VERSION 5.7 ;
  NOWIREEXTENSIONATPIN ON ;
  DIVIDERCHAR "/" ;
  BUSBITCHARS "[]" ;
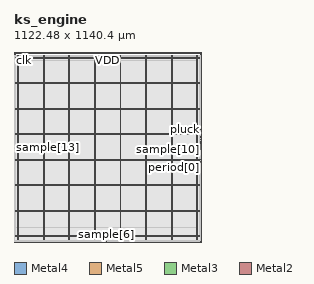
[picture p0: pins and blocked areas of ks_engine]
MACRO ks_engine
  CLASS BLOCK ;
  FOREIGN ks_engine ;
  ORIGIN 0.000 0.000 ;
  SIZE 1122.480 BY 1140.400 ;
  PIN VDD
    DIRECTION INOUT ;
    USE POWER ;
    PORT
      LAYER Metal4 ;
        RECT 22.240 15.380 23.840 1121.420 ;
    END
    PORT
      LAYER Metal4 ;
        RECT 175.840 15.380 177.440 1121.420 ;
    END
    PORT
      LAYER Metal4 ;
        RECT 329.440 15.380 331.040 1121.420 ;
    END
    PORT
      LAYER Metal4 ;
        RECT 483.040 15.380 484.640 1121.420 ;
    END
    PORT
      LAYER Metal4 ;
        RECT 636.640 15.380 638.240 1121.420 ;
    END
    PORT
      LAYER Metal4 ;
        RECT 790.240 15.380 791.840 1121.420 ;
    END
    PORT
      LAYER Metal4 ;
        RECT 943.840 15.380 945.440 1121.420 ;
    END
    PORT
      LAYER Metal4 ;
        RECT 1097.440 15.380 1099.040 1121.420 ;
    END
    PORT
      LAYER Metal5 ;
        RECT 6.720 31.530 1115.520 33.130 ;
    END
    PORT
      LAYER Metal5 ;
        RECT 6.720 184.710 1115.520 186.310 ;
    END
    PORT
      LAYER Metal5 ;
        RECT 6.720 337.890 1115.520 339.490 ;
    END
    PORT
      LAYER Metal5 ;
        RECT 6.720 491.070 1115.520 492.670 ;
    END
    PORT
      LAYER Metal5 ;
        RECT 6.720 644.250 1115.520 645.850 ;
    END
    PORT
      LAYER Metal5 ;
        RECT 6.720 797.430 1115.520 799.030 ;
    END
    PORT
      LAYER Metal5 ;
        RECT 6.720 950.610 1115.520 952.210 ;
    END
    PORT
      LAYER Metal5 ;
        RECT 6.720 1103.790 1115.520 1105.390 ;
    END
  END VDD
  PIN VSS
    DIRECTION INOUT ;
    USE GROUND ;
    PORT
      LAYER Metal4 ;
        RECT 25.540 15.380 27.140 1121.420 ;
    END
    PORT
      LAYER Metal4 ;
        RECT 179.140 15.380 180.740 1121.420 ;
    END
    PORT
      LAYER Metal4 ;
        RECT 332.740 15.380 334.340 1121.420 ;
    END
    PORT
      LAYER Metal4 ;
        RECT 486.340 15.380 487.940 1121.420 ;
    END
    PORT
      LAYER Metal4 ;
        RECT 639.940 15.380 641.540 1121.420 ;
    END
    PORT
      LAYER Metal4 ;
        RECT 793.540 15.380 795.140 1121.420 ;
    END
    PORT
      LAYER Metal4 ;
        RECT 947.140 15.380 948.740 1121.420 ;
    END
    PORT
      LAYER Metal4 ;
        RECT 1100.740 15.380 1102.340 1121.420 ;
    END
    PORT
      LAYER Metal5 ;
        RECT 6.720 34.830 1115.520 36.430 ;
    END
    PORT
      LAYER Metal5 ;
        RECT 6.720 188.010 1115.520 189.610 ;
    END
    PORT
      LAYER Metal5 ;
        RECT 6.720 341.190 1115.520 342.790 ;
    END
    PORT
      LAYER Metal5 ;
        RECT 6.720 494.370 1115.520 495.970 ;
    END
    PORT
      LAYER Metal5 ;
        RECT 6.720 647.550 1115.520 649.150 ;
    END
    PORT
      LAYER Metal5 ;
        RECT 6.720 800.730 1115.520 802.330 ;
    END
    PORT
      LAYER Metal5 ;
        RECT 6.720 953.910 1115.520 955.510 ;
    END
    PORT
      LAYER Metal5 ;
        RECT 6.720 1107.090 1115.520 1108.690 ;
    END
  END VSS
  PIN clk
    DIRECTION INPUT ;
    USE SIGNAL ;
    ANTENNAGATEAREA 4.738000 ;
    PORT
      LAYER Metal3 ;
        RECT 0.000 1114.400 0.560 1114.960 ;
    END
  END clk
  PIN period[0]
    DIRECTION INPUT ;
    USE SIGNAL ;
    ANTENNAGATEAREA 0.498500 ;
    PORT
      LAYER Metal3 ;
        RECT 1121.920 497.280 1122.480 497.840 ;
    END
  END period[0]
  PIN period[1]
    DIRECTION INPUT ;
    USE SIGNAL ;
    ANTENNAGATEAREA 0.498500 ;
    PORT
      LAYER Metal3 ;
        RECT 1121.920 495.040 1122.480 495.600 ;
    END
  END period[1]
  PIN period[2]
    DIRECTION INPUT ;
    USE SIGNAL ;
    ANTENNAGATEAREA 0.498500 ;
    PORT
      LAYER Metal3 ;
        RECT 1121.920 480.480 1122.480 481.040 ;
    END
  END period[2]
  PIN period[3]
    DIRECTION INPUT ;
    USE SIGNAL ;
    ANTENNAGATEAREA 0.498500 ;
    PORT
      LAYER Metal3 ;
        RECT 1121.920 478.240 1122.480 478.800 ;
    END
  END period[3]
  PIN period[4]
    DIRECTION INPUT ;
    USE SIGNAL ;
    ANTENNAGATEAREA 0.498500 ;
    PORT
      LAYER Metal3 ;
        RECT 1121.920 496.160 1122.480 496.720 ;
    END
  END period[4]
  PIN period[5]
    DIRECTION INPUT ;
    USE SIGNAL ;
    ANTENNAGATEAREA 0.498500 ;
    PORT
      LAYER Metal3 ;
        RECT 1121.920 479.360 1122.480 479.920 ;
    END
  END period[5]
  PIN period[6]
    DIRECTION INPUT ;
    USE SIGNAL ;
    ANTENNAGATEAREA 0.498500 ;
    PORT
      LAYER Metal3 ;
        RECT 1121.920 493.920 1122.480 494.480 ;
    END
  END period[6]
  PIN period[7]
    DIRECTION INPUT ;
    USE SIGNAL ;
    ANTENNAGATEAREA 0.498500 ;
    PORT
      LAYER Metal3 ;
        RECT 1121.920 481.600 1122.480 482.160 ;
    END
  END period[7]
  PIN period[8]
    DIRECTION INPUT ;
    USE SIGNAL ;
    ANTENNAGATEAREA 0.498500 ;
    PORT
      LAYER Metal3 ;
        RECT 1121.920 474.880 1122.480 475.440 ;
    END
  END period[8]
  PIN period[9]
    DIRECTION INPUT ;
    USE SIGNAL ;
    ANTENNAGATEAREA 0.498500 ;
    PORT
      LAYER Metal3 ;
        RECT 1121.920 476.000 1122.480 476.560 ;
    END
  END period[9]
  PIN pluck
    DIRECTION INPUT ;
    USE SIGNAL ;
    ANTENNAGATEAREA 0.498500 ;
    PORT
      LAYER Metal3 ;
        RECT 1121.920 673.120 1122.480 673.680 ;
    END
  END pluck
  PIN rst_n
    DIRECTION INPUT ;
    USE SIGNAL ;
    ANTENNAGATEAREA 0.498500 ;
    PORT
      LAYER Metal3 ;
        RECT 1121.920 555.520 1122.480 556.080 ;
    END
  END rst_n
  PIN sample[0]
    DIRECTION OUTPUT ;
    USE SIGNAL ;
    ANTENNADIFFAREA 1.986000 ;
    PORT
      LAYER Metal3 ;
        RECT 1121.920 583.520 1122.480 584.080 ;
    END
  END sample[0]
  PIN sample[10]
    DIRECTION OUTPUT ;
    USE SIGNAL ;
    ANTENNADIFFAREA 1.986000 ;
    PORT
      LAYER Metal3 ;
        RECT 1121.920 600.320 1122.480 600.880 ;
    END
  END sample[10]
  PIN sample[11]
    DIRECTION OUTPUT ;
    USE SIGNAL ;
    ANTENNADIFFAREA 1.986000 ;
    PORT
      LAYER Metal3 ;
        RECT 1121.920 599.200 1122.480 599.760 ;
    END
  END sample[11]
  PIN sample[12]
    DIRECTION OUTPUT ;
    USE SIGNAL ;
    ANTENNADIFFAREA 1.986000 ;
    PORT
      LAYER Metal3 ;
        RECT 1121.920 624.960 1122.480 625.520 ;
    END
  END sample[12]
  PIN sample[13]
    DIRECTION OUTPUT ;
    USE SIGNAL ;
    ANTENNADIFFAREA 1.986000 ;
    PORT
      LAYER Metal3 ;
        RECT 0.000 567.840 0.560 568.400 ;
    END
  END sample[13]
  PIN sample[14]
    DIRECTION OUTPUT ;
    USE SIGNAL ;
    ANTENNADIFFAREA 1.986000 ;
    PORT
      LAYER Metal3 ;
        RECT 1121.920 612.640 1122.480 613.200 ;
    END
  END sample[14]
  PIN sample[15]
    DIRECTION OUTPUT ;
    USE SIGNAL ;
    ANTENNADIFFAREA 1.986000 ;
    PORT
      LAYER Metal3 ;
        RECT 1121.920 631.680 1122.480 632.240 ;
    END
  END sample[15]
  PIN sample[1]
    DIRECTION OUTPUT ;
    USE SIGNAL ;
    ANTENNADIFFAREA 1.986000 ;
    PORT
      LAYER Metal3 ;
        RECT 1121.920 573.440 1122.480 574.000 ;
    END
  END sample[1]
  PIN sample[2]
    DIRECTION OUTPUT ;
    USE SIGNAL ;
    ANTENNADIFFAREA 1.986000 ;
    PORT
      LAYER Metal3 ;
        RECT 0.000 555.520 0.560 556.080 ;
    END
  END sample[2]
  PIN sample[3]
    DIRECTION OUTPUT ;
    USE SIGNAL ;
    ANTENNADIFFAREA 1.986000 ;
    PORT
      LAYER Metal3 ;
        RECT 0.000 563.360 0.560 563.920 ;
    END
  END sample[3]
  PIN sample[4]
    DIRECTION OUTPUT ;
    USE SIGNAL ;
    ANTENNADIFFAREA 1.986000 ;
    PORT
      LAYER Metal3 ;
        RECT 1121.920 584.640 1122.480 585.200 ;
    END
  END sample[4]
  PIN sample[5]
    DIRECTION OUTPUT ;
    USE SIGNAL ;
    ANTENNADIFFAREA 1.986000 ;
    PORT
      LAYER Metal3 ;
        RECT 1121.920 560.000 1122.480 560.560 ;
    END
  END sample[5]
  PIN sample[6]
    DIRECTION OUTPUT ;
    USE SIGNAL ;
    ANTENNADIFFAREA 1.986000 ;
    PORT
      LAYER Metal2 ;
        RECT 556.640 0.000 557.200 0.560 ;
    END
  END sample[6]
  PIN sample[7]
    DIRECTION OUTPUT ;
    USE SIGNAL ;
    ANTENNADIFFAREA 1.986000 ;
    PORT
      LAYER Metal3 ;
        RECT 1121.920 565.600 1122.480 566.160 ;
    END
  END sample[7]
  PIN sample[8]
    DIRECTION OUTPUT ;
    USE SIGNAL ;
    ANTENNADIFFAREA 1.986000 ;
    PORT
      LAYER Metal3 ;
        RECT 1121.920 588.000 1122.480 588.560 ;
    END
  END sample[8]
  PIN sample[9]
    DIRECTION OUTPUT ;
    USE SIGNAL ;
    ANTENNADIFFAREA 1.986000 ;
    PORT
      LAYER Metal3 ;
        RECT 1121.920 558.880 1122.480 559.440 ;
    END
  END sample[9]
  PIN sample_tick
    DIRECTION INPUT ;
    USE SIGNAL ;
    ANTENNAGATEAREA 0.498500 ;
    PORT
      LAYER Metal3 ;
        RECT 1121.920 580.160 1122.480 580.720 ;
    END
  END sample_tick
  OBS
      LAYER Nwell ;
        RECT 6.290 15.250 1115.950 1121.550 ;
      LAYER Metal1 ;
        RECT 6.720 15.380 1115.520 1121.420 ;
      LAYER Metal2 ;
        RECT 0.140 0.860 1115.940 1121.310 ;
        RECT 0.140 0.560 556.340 0.860 ;
        RECT 557.500 0.560 1115.940 0.860 ;
      LAYER Metal3 ;
        RECT 0.090 1115.260 1121.920 1121.260 ;
        RECT 0.860 1114.100 1121.920 1115.260 ;
        RECT 0.090 673.980 1121.920 1114.100 ;
        RECT 0.090 672.820 1121.620 673.980 ;
        RECT 0.090 632.540 1121.920 672.820 ;
        RECT 0.090 631.380 1121.620 632.540 ;
        RECT 0.090 625.820 1121.920 631.380 ;
        RECT 0.090 624.660 1121.620 625.820 ;
        RECT 0.090 613.500 1121.920 624.660 ;
        RECT 0.090 612.340 1121.620 613.500 ;
        RECT 0.090 601.180 1121.920 612.340 ;
        RECT 0.090 598.900 1121.620 601.180 ;
        RECT 0.090 588.860 1121.920 598.900 ;
        RECT 0.090 587.700 1121.620 588.860 ;
        RECT 0.090 585.500 1121.920 587.700 ;
        RECT 0.090 583.220 1121.620 585.500 ;
        RECT 0.090 581.020 1121.920 583.220 ;
        RECT 0.090 579.860 1121.620 581.020 ;
        RECT 0.090 574.300 1121.920 579.860 ;
        RECT 0.090 573.140 1121.620 574.300 ;
        RECT 0.090 568.700 1121.920 573.140 ;
        RECT 0.860 567.540 1121.920 568.700 ;
        RECT 0.090 566.460 1121.920 567.540 ;
        RECT 0.090 565.300 1121.620 566.460 ;
        RECT 0.090 564.220 1121.920 565.300 ;
        RECT 0.860 563.060 1121.920 564.220 ;
        RECT 0.090 560.860 1121.920 563.060 ;
        RECT 0.090 558.580 1121.620 560.860 ;
        RECT 0.090 556.380 1121.920 558.580 ;
        RECT 0.860 555.220 1121.620 556.380 ;
        RECT 0.090 498.140 1121.920 555.220 ;
        RECT 0.090 493.620 1121.620 498.140 ;
        RECT 0.090 482.460 1121.920 493.620 ;
        RECT 0.090 477.940 1121.620 482.460 ;
        RECT 0.090 476.860 1121.920 477.940 ;
        RECT 0.090 474.580 1121.620 476.860 ;
        RECT 0.090 8.540 1121.920 474.580 ;
      LAYER Metal4 ;
        RECT 8.540 32.010 21.940 1114.310 ;
        RECT 24.140 32.010 25.240 1114.310 ;
        RECT 27.440 32.010 175.540 1114.310 ;
        RECT 177.740 32.010 178.840 1114.310 ;
        RECT 181.040 32.010 329.140 1114.310 ;
        RECT 331.340 32.010 332.440 1114.310 ;
        RECT 334.640 32.010 482.740 1114.310 ;
        RECT 484.940 32.010 486.040 1114.310 ;
        RECT 488.240 32.010 636.340 1114.310 ;
        RECT 638.540 32.010 639.640 1114.310 ;
        RECT 641.840 32.010 789.940 1114.310 ;
        RECT 792.140 32.010 793.240 1114.310 ;
        RECT 795.440 32.010 943.540 1114.310 ;
        RECT 945.740 32.010 946.840 1114.310 ;
        RECT 949.040 32.010 1097.140 1114.310 ;
        RECT 1099.340 32.010 1100.440 1114.310 ;
        RECT 1102.640 32.010 1114.260 1114.310 ;
      LAYER Metal5 ;
        RECT 8.460 956.110 1103.140 1091.470 ;
        RECT 8.460 952.810 1103.140 953.310 ;
        RECT 8.460 802.930 1103.140 950.010 ;
        RECT 8.460 799.630 1103.140 800.130 ;
        RECT 8.460 649.750 1103.140 796.830 ;
        RECT 8.460 646.450 1103.140 646.950 ;
        RECT 8.460 496.570 1103.140 643.650 ;
        RECT 8.460 493.270 1103.140 493.770 ;
        RECT 8.460 343.390 1103.140 490.470 ;
        RECT 8.460 340.090 1103.140 340.590 ;
        RECT 8.460 190.210 1103.140 337.290 ;
        RECT 8.460 186.910 1103.140 187.410 ;
        RECT 8.460 87.530 1103.140 184.110 ;
  END
END ks_engine
END LIBRARY

